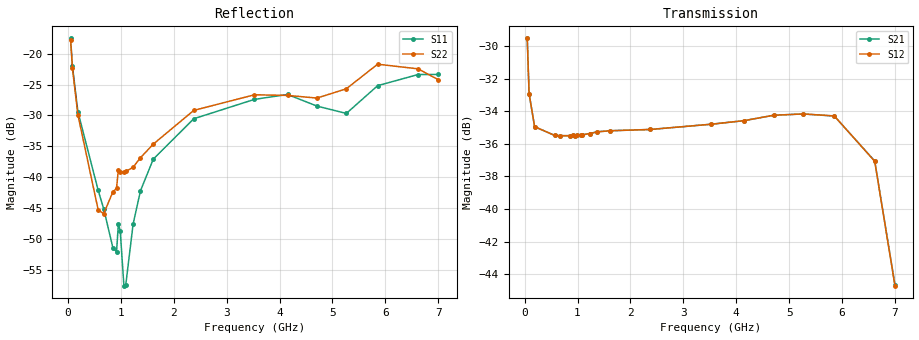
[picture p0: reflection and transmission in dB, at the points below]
! Integrated Device Technology
! Corporate Headquarters
! 6024 Silver Creek Valley Road
! San Jose, CA 95138  USA
! Phone:  1-408-284-8200
! Toll Free:  1-800-223-1366
! Webpage:  http://www.idt.com/
! Timing and RF Division
! 515 Groton Road, Suite 102
! Westford, MA 01886-6024
! Device:  F2258
! Description: Voltage Variable RF Attenuator
! Frequency:  50.0 -  6000.00 MHz
! Package:  3x3 mm Thin QFN Plastic Package: 16 pin
! Ports:  2 RF, 2 DC
!  Pin  1  = NC
!  Pin  2  = NC
!  Pin  3  = RF2  = Port 2
!  Pin  4  = GND
!  Pin  5  = Vdd
!  Pin  6  = NC
!  Pin  7  = VCTRL
!  Pin  8  = NC
!  Pin  9  = GND
!  Pin 10  = RF1  = Port 1
!  Pin 11  = NC
!  Pin 12  = NC
!  Pin 13  = NC
!  Pin 14  = NC
!  Pin 15  = NC
!  Pin 16  = NC
! Vcntrl:  2.470 Volts
! Vdd:  +3.300 Volts
! Current:  1.147 mA
! Data:  The device was measured on a the F2258 evaluation board which has
!  individual transmission lines to the RF pins.  Data was collected
!  using a calibrated network analyzer.  The evaluation board was
!  de-embedded using a TRL calibration technique.
!  The reference plane is the edge of the package pin.
! Misc:  SN 10
!  Action Tracker AT0285
! Date Measured:  2014-12-10
! Date:  2016-01-13  MJV
! Note:
!  Integrated Device Technology supplies this data as a sample of measured
!  data at the package pin for this product.  Your particular data for this
!  product may vary.
!  Data was taken at 25 degrees C.
!  Integrated Device Technology reserves the right to change this data at anytime.
!Freq_(GHz)  S11M_(dB)  S11P_(deg)  S21M_(dB)  S21P_(deg)  S12M_(dB)  S12P_(deg)  S22M_(dB)  S22P_(deg)
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# GHz S dB R 50
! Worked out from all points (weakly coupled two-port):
!   201 points, 50 MHz to 7 GHz, reference 50 ohm
!   highest |S21| = -29.54 dB at 50 MHz (marker M1); lowest = -44.6 dB at 7 GHz (marker M2)
!   lowest |S11| = -57.5 dB at 1.058 GHz (marker M3), VSWR 1.00, Z = 49.9 + j0.0586 ohm
!   |S11| at or under -10 dB: start of sweep to end of sweep
!   |S22| runs from -45.9 to -17.8 dB; largest |S21 - S12| = 8.6e-05
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0.05  -17.55 -111.0  -29.54 -68.7  -29.54 -68.7  -17.75 -111.8
0.08475  -21.98 -107.4  -32.92 -48.9  -32.92 -49.0  -22.38 -108.6
0.189  -29.41 -109.5  -34.95 -24.8  -34.95 -24.9  -29.92 -112.8
0.57125  -42.07 -125.0  -35.49 -10.4  -35.49 -10.4  -45.22 -171.3
0.6755  -45.06 -132.6  -35.50 -9.4  -35.50 -9.4  -45.86 154.6
0.84925  -51.34 -175.4  -35.50 -8.5  -35.50 -8.5  -42.35 129.5
0.91875  -52.01 151.3  -35.49 -8.3  -35.49 -8.3  -41.74 126.2
0.9535  -47.50 -163.1  -35.50 -8.2  -35.51 -8.2  -38.73 128.6
0.98825  -48.59 -174.7  -35.48 -8.1  -35.48 -8.1  -39.05 126.6
1.05775  -57.48 153.9  -35.47 -7.9  -35.47 -7.9  -39.17 113.7
1.0925  -57.39 122.4  -35.45 -7.8  -35.45 -7.8  -39.04 109.6
1.2315  -47.56 46.5  -35.37 -7.8  -35.37 -7.8  -38.36 88.3
1.3705  -42.17 37.4  -35.26 -8.2  -35.27 -8.3  -36.82 74.1
1.61375  -37.04 32.9  -35.20 -9.5  -35.20 -9.5  -34.62 58.7
2.37825  -30.53 48.2  -35.12 -13.1  -35.12 -13.0  -29.18 46.4
3.525  -27.40 91.7  -34.80 -19.4  -34.80 -19.4  -26.66 69.4
4.1505  -26.61 105.0  -34.58 -23.8  -34.58 -23.8  -26.76 76.6
4.7065  -28.48 95.7  -34.25 -28.5  -34.25 -28.5  -27.19 60.4
5.2625  -29.67 54.4  -34.17 -34.7  -34.17 -34.7  -25.69 23.2
5.85325  -25.19 29.9  -34.30 -45.3  -34.29 -45.3  -21.72 -1.3
6.61775  -23.39 49.7  -37.05 -68.6  -37.07 -68.6  -22.47 -43.2
7  -23.37 84.5  -44.62 -61.4  -44.69 -60.8  -24.22 -130.2
